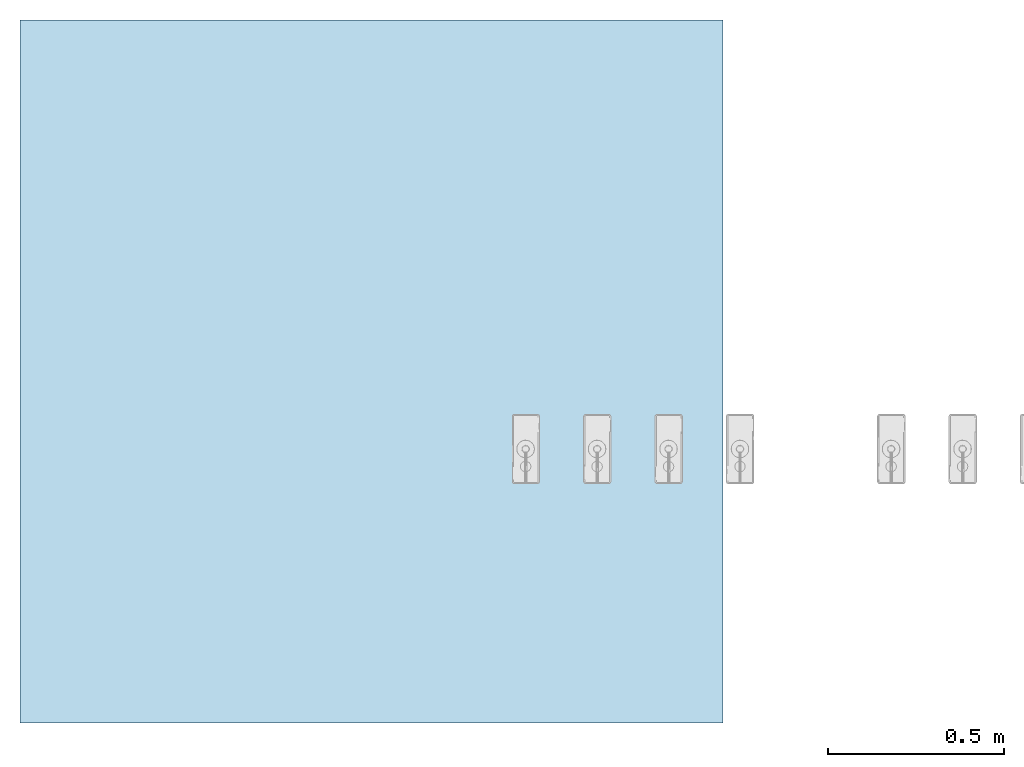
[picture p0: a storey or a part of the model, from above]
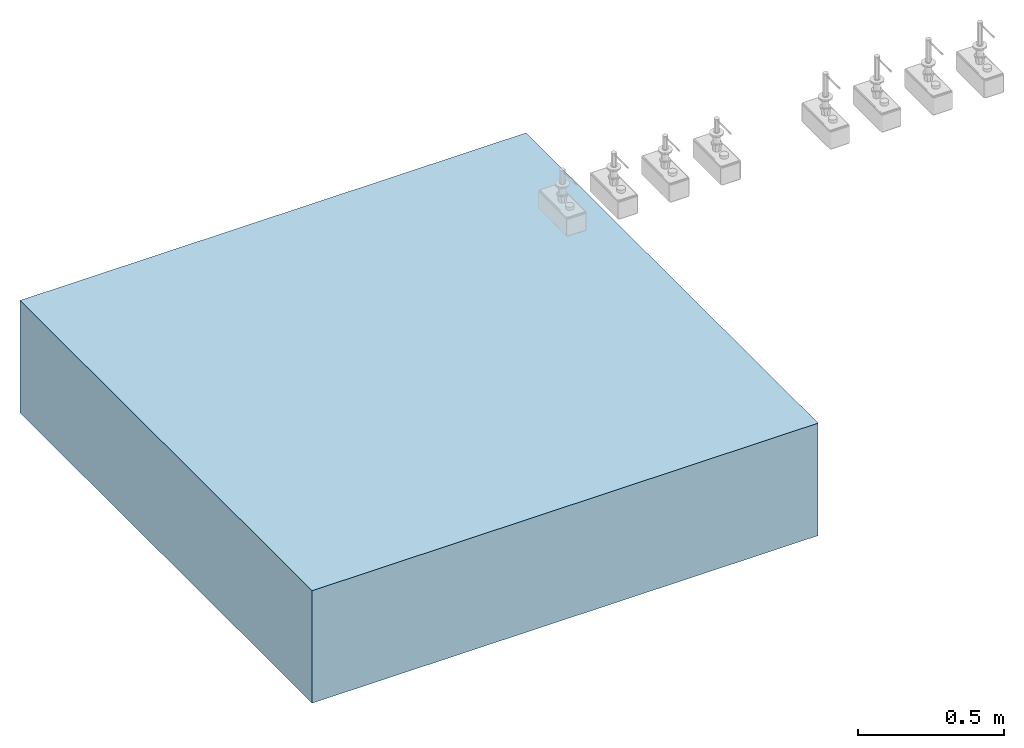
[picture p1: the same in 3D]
Properties of the parts of a building model (IFC2X3)

# File
Description: ViewDefinition [CoordinationView_V2.0], RevitIdentifiers [VersionGUID: f84aafc0-c841-4e46-b12c-eb19207ad10d, NumberOfSaves: 67], CoordinateReference [CoordinateBase: Shared Coordinates]
File name: S282S285_ProductSummary.ifc
Time: 2024-10-04T10:10:57
Written by: ODA IFC SDK 22.8
Made in: 22.1.70.9 - IFC 22.7.0.0 - Default UI

# IfcProject, Project Number
LongName: Project Name; Phase: Awaiting Approval

# IfcSite, Default
RefLatitude: 51, 30, 23, 112487; RefLongitude: 0, -7, -37, -956022; RefElevation: 0 mm

# IfcBuilding, n/a
LongName: n/a
Pset_BuildingCommon - NumberOfStoreys: 1

# IfcBuildingStorey: Level:Circle Head - Project Datum (2)
In: n/a
Pset_AirSideSystemInformation - sets with these values: 2
Name | LongName = Name | Elevation (mm)
Level 0 | Level 0 | 0
Level 1 | Level 1 | 4000

# IfcBuildingElementProxy: DBLTD_Duten_SoapDispensers_S282S285:Short Dispenser Brass, DBLTD_Duten_SoapDispensers_S282S285:Short Dispenser Brass:452828
In: Level 0
Type - PredefinedType: USERDEFINED; Classification: C1030210 Uniformat (Uniformat); Material: <Unnamed>, DBLTD_Duten_Metal_BrushedBrass
Type - Pset_BuildingElementProxyCommon - Reference: n/a
Type - Pset_ElementShading - Color: Defined by Finish
Type - Pset_ManufacturerTypeInformation - ModelReference: Short Dispenser Brass; Manufacturer: Duten
Type - Pset_ProductRequirements - Name: Soap Dispenser
Type - Pset_QuantityTakeOff - Reference: n/a
Type - Pset_ProvisionForVoid - Shape: Cylindrical
Pset_BuildingElementProxyCommon - sets with these values: 2

# IfcBuildingElementProxy: DBLTD_Duten_SoapDispensers_S282S285:Short Dispenser Brushed Stainless Steel, DBLTD_Duten_SoapDispensers_S282S285:Short Dispenser Brushed Stainless Steel:452876
In: Level 0
Type - PredefinedType: USERDEFINED; Classification: C1030210 Uniformat (Uniformat); Material: <Unnamed>, DBLTD_Duten_Metal_BrushedStainlessSteel
Type - Pset_BuildingElementProxyCommon - Reference: n/a
Type - Pset_ElementShading - Color: Defined by Finish
Type - Pset_ManufacturerTypeInformation - ModelReference: Short Dispenser Brushed Stainless Steel; Manufacturer: Duten
Type - Pset_ProductRequirements - Name: Soap Dispenser
Type - Pset_QuantityTakeOff - Reference: n/a
Type - Pset_ProvisionForVoid - Shape: Cylindrical
Pset_BuildingElementProxyCommon - sets with these values: 2

# IfcBuildingElementProxy: DBLTD_Duten_SoapDispensers_S282S285:Short Dispenser Chrome, DBLTD_Duten_SoapDispensers_S282S285:Short Dispenser Chrome:452895
In: Level 0
Type - PredefinedType: USERDEFINED; Classification: C1030210 Uniformat (Uniformat); Material: <Unnamed>, DBLTD_Duten_Metal_Chrome
Type - Pset_BuildingElementProxyCommon - Reference: n/a
Type - Pset_ElementShading - Color: Defined by Finish
Type - Pset_ManufacturerTypeInformation - ModelReference: Short Dispenser Chrome; Manufacturer: Duten
Type - Pset_ProductRequirements - Name: Soap Dispenser
Type - Pset_QuantityTakeOff - Reference: n/a
Type - Pset_ProvisionForVoid - Shape: Cylindrical
Pset_BuildingElementProxyCommon - sets with these values: 2

# IfcBuildingElementProxy: DBLTD_Duten_SoapDispensers_S282S285:Short Dispenser Matte Black, DBLTD_Duten_SoapDispensers_S282S285:Short Dispenser Matte Black:452911
In: Level 0
Type - PredefinedType: USERDEFINED; Classification: C1030210 Uniformat (Uniformat); Material: <Unnamed>, DBLTD_Duten_Metal_MatteBlack
Type - Pset_BuildingElementProxyCommon - Reference: n/a
Type - Pset_ElementShading - Color: Defined by Finish
Type - Pset_ManufacturerTypeInformation - ModelReference: Short Dispenser Matte Black; Manufacturer: Duten
Type - Pset_ProductRequirements - Name: Soap Dispenser
Type - Pset_QuantityTakeOff - Reference: n/a
Type - Pset_ProvisionForVoid - Shape: Cylindrical
Pset_BuildingElementProxyCommon - sets with these values: 2

# IfcBuildingElementProxy: DBLTD_Duten_SoapDispensers_S282S285:Tall Dispenser Brass, DBLTD_Duten_SoapDispensers_S282S285:Tall Dispenser Brass:452976
In: Level 0
Type - PredefinedType: USERDEFINED; Classification: C1030210 Uniformat (Uniformat); Material: <Unnamed>, DBLTD_Duten_Metal_BrushedBrass
Type - Pset_BuildingElementProxyCommon - Reference: n/a
Type - Pset_ElementShading - Color: Defined by Finish
Type - Pset_ManufacturerTypeInformation - ModelReference: Tall Dispenser Brass; Manufacturer: Duten
Type - Pset_ProductRequirements - Name: Soap Dispenser
Type - Pset_QuantityTakeOff - Reference: n/a
Type - Pset_ProvisionForVoid - Shape: Cylindrical
Pset_BuildingElementProxyCommon - sets with these values: 2

# IfcBuildingElementProxy: DBLTD_Duten_SoapDispensers_S282S285:Tall Dispenser Brushed Stainless Steel, DBLTD_Duten_SoapDispensers_S282S285:Tall Dispenser Brushed Stainless Steel:452978
In: Level 0
Type - PredefinedType: USERDEFINED; Classification: C1030210 Uniformat (Uniformat); Material: <Unnamed>, DBLTD_Duten_Metal_BrushedStainlessSteel
Type - Pset_BuildingElementProxyCommon - Reference: n/a
Type - Pset_ElementShading - Color: Defined by Finish
Type - Pset_ManufacturerTypeInformation - ModelReference: Tall Dispenser Brushed Stainless Steel; Manufacturer: Duten
Type - Pset_ProductRequirements - Name: Soap Dispenser
Type - Pset_QuantityTakeOff - Reference: n/a
Type - Pset_ProvisionForVoid - Shape: Cylindrical
Pset_BuildingElementProxyCommon - sets with these values: 2

# IfcBuildingElementProxy: DBLTD_Duten_SoapDispensers_S282S285:Tall Dispenser Chrome, DBLTD_Duten_SoapDispensers_S282S285:Tall Dispenser Chrome:452979
In: Level 0
Type - PredefinedType: USERDEFINED; Classification: C1030210 Uniformat (Uniformat); Material: <Unnamed>, DBLTD_Duten_Metal_Chrome
Type - Pset_BuildingElementProxyCommon - Reference: n/a
Type - Pset_ElementShading - Color: Defined by Finish
Type - Pset_ManufacturerTypeInformation - ModelReference: Tall Dispenser Chrome; Manufacturer: Duten
Type - Pset_ProductRequirements - Name: Soap Dispenser
Type - Pset_QuantityTakeOff - Reference: n/a
Type - Pset_ProvisionForVoid - Shape: Cylindrical
Pset_BuildingElementProxyCommon - sets with these values: 2

# IfcBuildingElementProxy: DBLTD_Duten_SoapDispensers_S282S285:Tall Dispenser Matte Black, DBLTD_Duten_SoapDispensers_S282S285:Tall Dispenser Matte Black:452980
In: Level 0
Type - PredefinedType: USERDEFINED; Classification: C1030210 Uniformat (Uniformat); Material: <Unnamed>, DBLTD_Duten_Metal_MatteBlack
Type - Pset_BuildingElementProxyCommon - Reference: n/a
Type - Pset_ElementShading - Color: Defined by Finish
Type - Pset_ManufacturerTypeInformation - ModelReference: Tall Dispenser Matte Black; Manufacturer: Duten
Type - Pset_ProductRequirements - Name: Soap Dispenser
Type - Pset_QuantityTakeOff - Reference: n/a
Type - Pset_ProvisionForVoid - Shape: Cylindrical
Pset_BuildingElementProxyCommon - sets with these values: 2

# IfcSlab: Floor:Floor-Grnd-Susp_65Scr-80Ins-100Blk-75PC, Floor:Floor-Grnd-Susp_65Scr-80Ins-100Blk-75PC:421633
In: Level 0
Type - PredefinedType: FLOOR; Material: Concrete, Sand/Cement Screed 65 mm, Rigid insulation 80 mm, Air 150 mm, Concrete Masonry, Floor Block 100 mm, Concrete, Precast 75 mm
Type - Pset_SlabCommon - IsExternal: no; ThermalTransmittance: 0.117438 kg/K/s3
Pset_QuantityTakeOff - Reference: Floor-Grnd-Susp_65Scr-80Ins-100Blk-75PC; sets with these values: 2
Pset_SlabCommon - Reference: Floor-Grnd-Susp_65Scr-80Ins-100Blk-75PC; LoadBearing: no; PitchAngle: 0 deg
